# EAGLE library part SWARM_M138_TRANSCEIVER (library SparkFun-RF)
Swarm M138 Modem Description: A satellite transceiver based on the mPCIe standard.

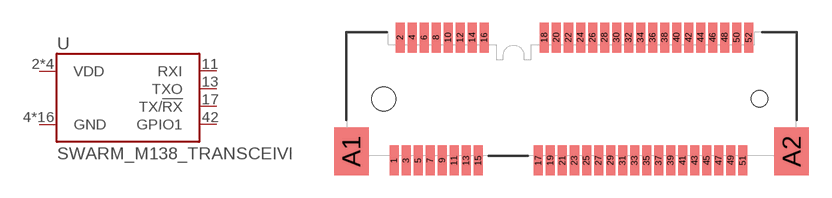
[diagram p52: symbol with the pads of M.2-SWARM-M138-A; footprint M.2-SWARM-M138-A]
Designator prefix U

## SWARM_M138_TRANSCEIVER_MAIN (PROD_ID: CONN-16558)  [M.2-SWARM-M138-A]
2  VDD  pwr
4  GND  pwr
9  GND  pwr
11  RXI  in
13  TXO  out
15  GND  pwr
17  TX/!RX!  out
18  GND  pwr
21  GND  pwr
26  GND  pwr
27  GND  pwr
29  GND  pwr
34  GND  pwr
35  GND  pwr
37  GND  pwr
39  VDD  pwr
40  GND  pwr
41  VDD  pwr
42  GPIO1
43  GND  pwr
50  GND  pwr
52  VDD  pwr
A1  GND  pwr
A2  GND  pwr

## Footprint M.2-SWARM-M138-A (pad centres in mm)
smd 0.6 x 2: 1 -11.8,-4.1; 2 -11.4,4.1; 3 -11,-4.1; 4 -10.6,4.1; 5 -10.2,-4.1; 6 -9.8,4.1; 7 -9.4,-4.1; 8 -9,4.1; 9 -8.6,-4.1; 10 -8.2,4.1; 11 -7.8,-4.1; 12 -7.4,4.1; 13 -7,-4.1; 14 -6.6,4.1; 15 -6.2,-4.1; 16 -5.8,4.1; 17 -2.2,-4.1; 18 -1.8,4.1; 19 -1.4,-4.1; 20 -1,4.1; 21 -0.6,-4.1; 22 -0.2,4.1; 23 0.2,-4.1; 24 0.6,4.1; 25 1,-4.1; 26 1.4,4.1; 27 1.8,-4.1; 28 2.2,4.1; 29 2.6,-4.1; 30 3,4.1; 31 3.4,-4.1; 32 3.8,4.1; 33 4.2,-4.1; 34 4.6,4.1; 35 5,-4.1; 36 5.4,4.1; 37 5.8,-4.1; 38 6.2,4.1; 39 6.6,-4.1; 40 7,4.1; 41 7.4,-4.1; 42 7.8,4.1; 43 8.2,-4.1; 44 8.6,4.1; 45 9,-4.1; 46 9.4,4.1; 47 9.8,-4.1; 48 10.2,4.1; 49 10.6,-4.1; 50 11,4.1; 51 11.4,-4.1; 52 11.8,4.1
smd 2.3 x 3.2: A1 -14.65,-3.5; A2 14.65,-3.5
hole 1.1 at 12.5,0
hole 1.6 at -12.5,0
